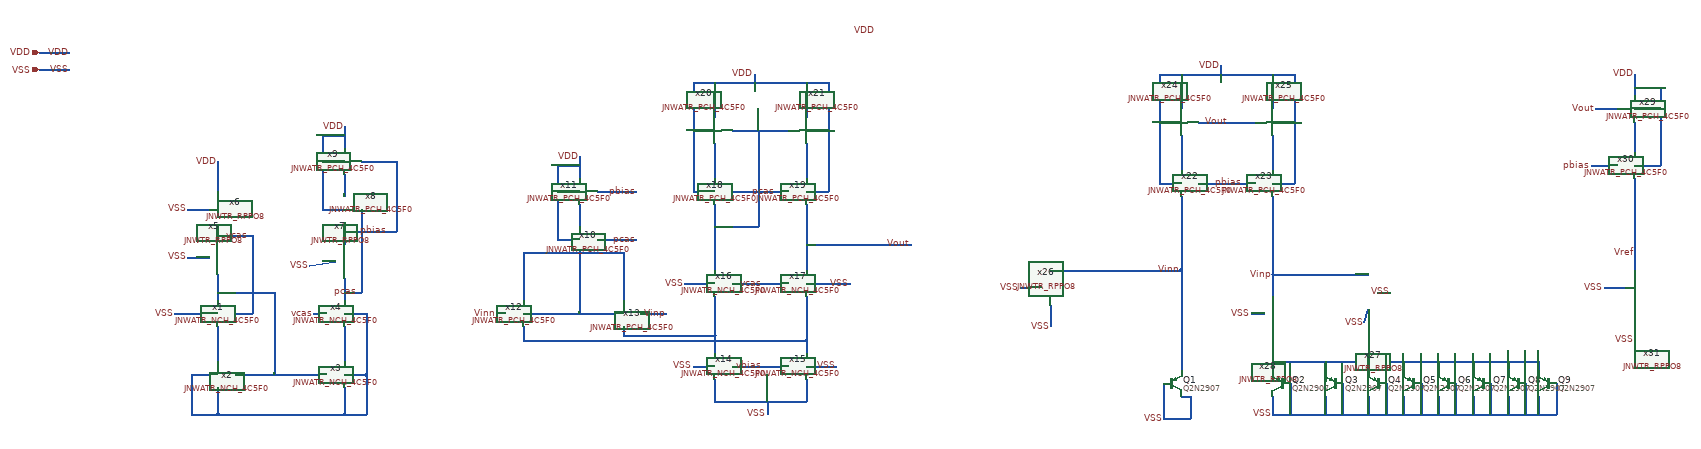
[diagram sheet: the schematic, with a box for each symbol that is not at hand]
v {xschem version=3.4.6 file_version=1.2}
G {}
K {}
V {}
S {sd}
E {}
N -50 30 -50 110 {lab=#net1}
N -10 140 200 140 {lab=#net2}
N -50 -90 -50 -30 {lab=#net2}
N -50 -200 -50 -170 {lab=vcas}
N 240 -80 240 -30 {lab=pcas}
N 240 -210 240 -160 {lab=pbias}
N 240 -320 240 -270 {lab=#net3}
N 240 30 240 110 {lab=#net4}
N -50 170 -50 230 {lab=#net5}
N -50 230 240 230 {lab=#net5}
N 240 170 240 220 {lab=#net5}
N 240 220 240 230 {lab=#net5}
N -110 140 -50 140 {lab=#net5}
N -110 140 -110 230 {lab=#net5}
N -110 230 -50 230 {lab=#net5}
N 240 140 290 140 {lab=#net5}
N 240 230 290 230 {lab=#net5}
N 290 140 290 230 {lab=#net5}
N 290 0 290 140 {lab=#net5}
N 240 0 290 0 {lab=#net5}
N -10 0 30 0 {lab=vcas}
N -50 -180 30 -180 {lab=vcas}
N 30 -180 30 0 {lab=vcas}
N -50 -50 80 -50 {lab=#net2}
N 80 -50 80 140 {lab=#net2}
N -460 -560 -430 -560 {lab=VSS}
N -430 -560 -390 -560 {lab=VSS}
N -120 -130 -70 -130 {lab=VSS}
N -120 -240 -70 -240 {lab=VSS}
N -150 0 -50 0 {lab=VSS}
N 160 -110 220 -120 {lab=VSS}
N -460 -600 -390 -600 {lab=VDD}
N 240 -430 240 -380 {lab=VDD}
N 190 -410 240 -410 {lab=VDD}
N 190 -410 190 -240 {lab=VDD}
N 190 -240 240 -240 {lab=VDD}
N 190 -350 240 -350 {lab=VDD}
N 280 -350 360 -350 {lab=pbias}
N 360 -350 360 -190 {lab=pbias}
N 240 -190 360 -190 {lab=pbias}
N 280 -240 280 -50 {lab=pcas}
N 240 -50 280 -50 {lab=pcas}
N -50 -350 -50 -280 {lab=VDD}
N 170 0 200 0 {lab=vcas}
N 780 -250 780 -200 {lab=#net6}
N 780 -360 780 -310 {lab=VDD}
N 730 -340 780 -340 {lab=VDD}
N 730 -340 730 -170 {lab=VDD}
N 730 -170 780 -170 {lab=VDD}
N 730 -280 780 -280 {lab=VDD}
N 820 -280 910 -280 {lab=pbias}
N 820 -170 910 -170 {lab=pcas}
N 780 -140 880 -140 {lab=#net7}
N 880 -140 880 -30 {lab=#net7}
N 660 -140 780 -140 {lab=#net7}
N 650 -140 650 -30 {lab=#net7}
N 650 -140 660 -140 {lab=#net7}
N 650 0 880 0 {lab=#net7}
N 780 -140 780 0 {lab=#net7}
N 920 0 980 0 {lab=Vinp}
N 590 0 610 0 {lab=Vinn}
N 1130 120 1260 120 {lab=vbias}
N 1130 -70 1260 -70 {lab=vcas}
N 1090 -40 1090 50 {lab=#net8}
N 1300 -40 1300 60 {lab=#net9}
N 1090 80 1090 90 {lab=#net8}
N 880 30 880 50 {lab=#net8}
N 1090 50 1090 80 {lab=#net8}
N 1300 60 1300 90 {lab=#net9}
N 880 50 1090 50 {lab=#net8}
N 650 30 650 50 {lab=#net9}
N 650 50 650 60 {lab=#net9}
N 650 60 1300 60 {lab=#net9}
N 1090 150 1090 200 {lab=VSS}
N 1090 200 1300 200 {lab=VSS}
N 1300 150 1300 200 {lab=VSS}
N 1090 -250 1090 -100 {lab=#net10}
N 1300 -250 1300 -100 {lab=Vout}
N 1130 -280 1260 -280 {lab=pcas}
N 1130 -420 1260 -420 {lab=#net10}
N 1300 -390 1300 -310 {lab=#net11}
N 1090 -390 1090 -310 {lab=#net12}
N 1190 -420 1190 -200 {lab=#net10}
N 1090 -200 1190 -200 {lab=#net10}
N 1040 -280 1090 -280 {lab=VDD}
N 1040 -520 1040 -280 {lab=VDD}
N 1040 -420 1090 -420 {lab=VDD}
N 1300 -280 1350 -280 {lab=VDD}
N 1350 -530 1350 -280 {lab=VDD}
N 1040 -530 1040 -520 {lab=VDD}
N 1300 -420 1350 -420 {lab=VDD}
N 1040 -530 1350 -530 {lab=VDD}
N 1090 -530 1090 -450 {lab=VDD}
N 1300 -530 1300 -450 {lab=VDD}
N 1180 -550 1180 -530 {lab=VDD}
N 1020 -70 1090 -70 {lab=VSS}
N 1300 -70 1400 -70 {lab=VSS}
N 1300 120 1370 120 {lab=VSS}
N 1040 120 1090 120 {lab=VSS}
N 1210 200 1210 230 {lab=VSS}
N 1300 -160 1540 -160 {lab=Vout}
N 2200 -300 2330 -300 {lab=pbias}
N 2200 -440 2330 -440 {lab=Vout}
N 2370 -410 2370 -330 {lab=#net13}
N 2160 -410 2160 -330 {lab=#net14}
N 2110 -300 2160 -300 {lab=VDD}
N 2110 -540 2110 -300 {lab=VDD}
N 2110 -440 2160 -440 {lab=VDD}
N 2370 -300 2420 -300 {lab=VDD}
N 2420 -550 2420 -300 {lab=VDD}
N 2110 -550 2110 -540 {lab=VDD}
N 2370 -440 2420 -440 {lab=VDD}
N 2110 -550 2420 -550 {lab=VDD}
N 2160 -550 2160 -470 {lab=VDD}
N 2370 -550 2370 -470 {lab=VDD}
N 2250 -570 2250 -550 {lab=VDD}
N 2160 -270 2160 -100 {lab=Vinn}
N 2370 -90 2590 -90 {lab=Vinp}
N 1860 -100 2160 -100 {lab=Vinn}
N 2370 -270 2370 -90 {lab=Vinp}
N 2370 -90 2370 -40 {lab=Vinp}
N 2160 -100 2160 130 {lab=Vinn}
N 2370 40 2370 130 {lab=#net15}
N 2980 110 2980 130 {lab=#net15}
N 2370 110 2980 110 {lab=#net15}
N 2830 110 2830 130 {lab=#net15}
N 2910 110 2910 130 {lab=#net15}
N 2750 110 2750 130 {lab=#net15}
N 2670 110 2670 130 {lab=#net15}
N 2590 110 2590 130 {lab=#net15}
N 2490 110 2490 130 {lab=#net15}
N 2370 190 2370 230 {lab=VSS}
N 2370 230 3020 230 {lab=VSS}
N 3020 160 3020 230 {lab=VSS}
N 2910 190 2910 230 {lab=VSS}
N 2980 190 2980 230 {lab=VSS}
N 2950 160 2950 230 {lab=VSS}
N 2870 160 2870 230 {lab=VSS}
N 2830 190 2830 230 {lab=VSS}
N 2750 190 2750 230 {lab=VSS}
N 2790 160 2790 230 {lab=VSS}
N 2670 190 2670 230 {lab=VSS}
N 2710 160 2710 230 {lab=VSS}
N 2590 190 2590 230 {lab=VSS}
N 2630 160 2630 230 {lab=VSS}
N 2530 160 2530 230 {lab=VSS}
N 2490 190 2490 230 {lab=VSS}
N 2410 160 2410 220 {lab=VSS}
N 2410 220 2410 230 {lab=VSS}
N 2120 160 2120 240 {lab=VSS}
N 2120 240 2170 240 {lab=VSS}
N 2160 190 2180 190 {lab=VSS}
N 2170 240 2180 240 {lab=VSS}
N 2180 190 2180 240 {lab=VSS}
N 1790 -60 1840 -60 {lab=VSS}
N 1860 -20 1860 30 {lab=VSS}
N 2320 0 2350 0 {lab=VSS}
N 2580 20 2590 -10 {lab=VSS}
N 2610 -50 2640 -50 {lab=VSS}
N 3200 -440 3200 -370 {lab=#net16}
N 3200 -550 3200 -500 {lab=VDD}
N 3200 -520 3260 -520 {lab=VDD}
N 3260 -520 3260 -340 {lab=VDD}
N 3200 -340 3260 -340 {lab=VDD}
N 3200 -470 3260 -470 {lab=VDD}
N 3110 -470 3160 -470 {lab=Vout}
N 3100 -340 3160 -340 {lab=pbias}
N 3200 -310 3200 -100 {lab=Vref}
N 3200 -20 3200 60 {lab=VSS}
N 3130 -60 3180 -60 {lab=VSS}
C {JNW_ATR_SKY130A/JNWATR_NCH_4C5F0.sym} -10 0 0 1 {name=x1 }
C {JNW_ATR_SKY130A/JNWATR_NCH_4C5F0.sym} -10 140 0 1 {name=x2 }
C {JNW_ATR_SKY130A/JNWATR_NCH_4C5F0.sym} 200 140 0 0 {name=x3 }
C {JNW_ATR_SKY130A/JNWATR_NCH_4C5F0.sym} 200 0 0 0 {name=x4 }
C {JNW_TR_SKY130A/JNWTR_RPPO8.sym} -50 -170 1 0 {name=x5 }
C {JNW_TR_SKY130A/JNWTR_RPPO8.sym} -50 -280 1 0 {name=x6 }
C {JNW_TR_SKY130A/JNWTR_RPPO8.sym} 240 -160 1 0 {name=x7 }
C {JNW_ATR_SKY130A/JNWATR_PCH_4C5F0.sym} 280 -240 0 1 {name=x8 }
C {JNW_ATR_SKY130A/JNWATR_PCH_4C5F0.sym} 280 -350 0 1 {name=x9 }
C {devices/ipin.sym} -460 -560 0 0 {name=p1 lab=VSS}
C {devices/lab_wire.sym} -390 -560 0 0 {name=p2 sig_type=std_logic lab=VSS}
C {devices/lab_wire.sym} -120 -240 0 0 {name=p3 sig_type=std_logic lab=VSS}
C {devices/lab_wire.sym} -120 -130 0 0 {name=p4 sig_type=std_logic lab=VSS}
C {devices/lab_wire.sym} -150 0 0 0 {name=p5 sig_type=std_logic lab=VSS}
C {devices/lab_wire.sym} 160 -110 0 0 {name=p6 sig_type=std_logic lab=VSS}
C {devices/ipin.sym} -460 -600 0 0 {name=p8 lab=VDD}
C {devices/lab_wire.sym} -390 -600 0 0 {name=p9 sig_type=std_logic lab=VDD}
C {devices/lab_wire.sym} 240 -430 0 0 {name=p10 sig_type=std_logic lab=VDD}
C {devices/lab_wire.sym} -50 -350 0 0 {name=p7 sig_type=std_logic lab=VDD}
C {devices/lab_wire.sym} 20 -180 0 0 {name=p11 sig_type=std_logic lab=vcas}
C {devices/lab_wire.sym} 170 0 0 0 {name=p12 sig_type=std_logic lab=vcas}
C {devices/lab_wire.sym} 270 -50 0 0 {name=p13 sig_type=std_logic lab=pcas}
C {devices/lab_wire.sym} 340 -190 0 0 {name=p14 sig_type=std_logic lab=pbias}
C {JNW_ATR_SKY130A/JNWATR_PCH_4C5F0.sym} 820 -170 0 1 {name=x10 }
C {JNW_ATR_SKY130A/JNWATR_PCH_4C5F0.sym} 820 -280 0 1 {name=x11 }
C {devices/lab_wire.sym} 780 -360 0 0 {name=p15 sig_type=std_logic lab=VDD}
C {devices/lab_wire.sym} 910 -280 0 0 {name=p16 sig_type=std_logic lab=pbias}
C {devices/lab_wire.sym} 910 -170 0 0 {name=p17 sig_type=std_logic lab=pcas}
C {JNW_ATR_SKY130A/JNWATR_PCH_4C5F0.sym} 610 0 0 0 {name=x12 }
C {JNW_ATR_SKY130A/JNWATR_PCH_4C5F0.sym} 920 0 0 1 {name=x13 }
C {devices/lab_wire.sym} 590 0 0 0 {name=p18 sig_type=std_logic lab=Vinn}
C {devices/lab_wire.sym} 980 0 0 0 {name=p19 sig_type=std_logic lab=Vinp}
C {JNW_ATR_SKY130A/JNWATR_NCH_4C5F0.sym} 1130 120 0 1 {name=x14 }
C {JNW_ATR_SKY130A/JNWATR_NCH_4C5F0.sym} 1260 120 0 0 {name=x15 }
C {JNW_ATR_SKY130A/JNWATR_NCH_4C5F0.sym} 1130 -70 0 1 {name=x16 }
C {JNW_ATR_SKY130A/JNWATR_NCH_4C5F0.sym} 1260 -70 0 0 {name=x17 }
C {JNW_ATR_SKY130A/JNWATR_PCH_4C5F0.sym} 1130 -280 0 1 {name=x18 }
C {JNW_ATR_SKY130A/JNWATR_PCH_4C5F0.sym} 1260 -280 0 0 {name=x19 }
C {JNW_ATR_SKY130A/JNWATR_PCH_4C5F0.sym} 1130 -420 0 1 {name=x20 }
C {JNW_ATR_SKY130A/JNWATR_PCH_4C5F0.sym} 1260 -420 0 0 {name=x21 }
C {devices/lab_wire.sym} 1180 -550 0 0 {name=p20 sig_type=std_logic lab=VDD}
C {devices/lab_wire.sym} 1020 -70 0 0 {name=p21 sig_type=std_logic lab=VSS}
C {devices/lab_wire.sym} 1400 -70 0 0 {name=p22 sig_type=std_logic lab=VSS}
C {devices/lab_wire.sym} 1040 120 0 0 {name=p23 sig_type=std_logic lab=VSS}
C {devices/lab_wire.sym} 1370 120 0 0 {name=p24 sig_type=std_logic lab=VSS}
C {devices/lab_wire.sym} 1210 230 0 0 {name=p25 sig_type=std_logic lab=VSS}
C {devices/lab_wire.sym} 1230 -280 0 0 {name=p26 sig_type=std_logic lab=pcas}
C {devices/lab_wire.sym} 1200 -70 0 0 {name=p27 sig_type=std_logic lab=vcas}
C {devices/lab_wire.sym} 1200 120 0 0 {name=p28 sig_type=std_logic lab=vbias}
C {devices/lab_wire.sym} 1540 -160 0 0 {name=p29 sig_type=std_logic lab=Vout}
C {JNW_ATR_SKY130A/JNWATR_PCH_4C5F0.sym} 2200 -300 0 1 {name=x22 }
C {JNW_ATR_SKY130A/JNWATR_PCH_4C5F0.sym} 2330 -300 0 0 {name=x23 }
C {JNW_ATR_SKY130A/JNWATR_PCH_4C5F0.sym} 2200 -440 0 1 {name=x24 }
C {JNW_ATR_SKY130A/JNWATR_PCH_4C5F0.sym} 2330 -440 0 0 {name=x25 }
C {devices/lab_wire.sym} 2250 -570 0 0 {name=p30 sig_type=std_logic lab=VDD}
C {devices/lab_wire.sym} 2300 -300 0 0 {name=p31 sig_type=std_logic lab=pbias}
C {JNW_TR_SKY130A/JNWTR_RPPO8.sym} 1860 -100 1 0 {name=x26 }
C {JNW_TR_SKY130A/JNWTR_RPPO8.sym} 2590 -90 3 1 {name=x27 }
C {JNW_TR_SKY130A/JNWTR_RPPO8.sym} 2370 -40 1 0 {name=x28 }
C {devices/pnp.sym} 2140 160 0 0 {name=Q1
model=Q2N2907
device=2N2907
footprint=TO92
area=1
m=1}
C {devices/pnp.sym} 2390 160 0 1 {name=Q2
model=Q2N2907
device=2N2907
footprint=TO92
area=1
m=1}
C {devices/pnp.sym} 2510 160 0 1 {name=Q3
model=Q2N2907
device=2N2907
footprint=TO92
area=1
m=1}
C {devices/pnp.sym} 2610 160 0 1 {name=Q4
model=Q2N2907
device=2N2907
footprint=TO92
area=1
m=1}
C {devices/pnp.sym} 2690 160 0 1 {name=Q5
model=Q2N2907
device=2N2907
footprint=TO92
area=1
m=1}
C {devices/pnp.sym} 2770 160 0 1 {name=Q6
model=Q2N2907
device=2N2907
footprint=TO92
area=1
m=1}
C {devices/pnp.sym} 2850 160 0 1 {name=Q7
model=Q2N2907
device=2N2907
footprint=TO92
area=1
m=1}
C {devices/pnp.sym} 2930 160 0 1 {name=Q8
model=Q2N2907
device=2N2907
footprint=TO92
area=1
m=1}
C {devices/pnp.sym} 3000 160 0 1 {name=Q9
model=Q2N2907
device=2N2907
footprint=TO92
area=1
m=1}
C {devices/lab_wire.sym} 1790 -60 0 0 {name=p32 sig_type=std_logic lab=VSS}
C {devices/lab_wire.sym} 1860 30 0 0 {name=p33 sig_type=std_logic lab=VSS}
C {devices/lab_wire.sym} 2120 240 0 0 {name=p34 sig_type=std_logic lab=VSS}
C {devices/lab_wire.sym} 2370 230 0 0 {name=p35 sig_type=std_logic lab=VSS}
C {devices/lab_wire.sym} 2320 0 0 0 {name=p36 sig_type=std_logic lab=VSS}
C {devices/lab_wire.sym} 2580 20 0 0 {name=p37 sig_type=std_logic lab=VSS}
C {devices/lab_wire.sym} 2640 -50 0 0 {name=p38 sig_type=std_logic lab=VSS}
C {devices/lab_wire.sym} 2270 -440 0 0 {name=p39 sig_type=std_logic lab=Vout}
C {devices/lab_wire.sym} 2370 -90 0 0 {name=p40 sig_type=std_logic lab=Vinp}
C {devices/lab_wire.sym} 2160 -100 0 0 {name=p41 sig_type=std_logic lab=Vinn}
C {JNW_ATR_SKY130A/JNWATR_PCH_4C5F0.sym} 3160 -470 0 0 {name=x29 }
C {JNW_ATR_SKY130A/JNWATR_PCH_4C5F0.sym} 3160 -340 0 0 {name=x30 }
C {devices/lab_wire.sym} 1460 -650 0 0 {name=p42 sig_type=std_logic lab=VDD}
C {devices/lab_wire.sym} 3200 -550 0 0 {name=p43 sig_type=std_logic lab=VDD}
C {devices/lab_wire.sym} 3110 -470 0 0 {name=p44 sig_type=std_logic lab=Vout}
C {devices/lab_wire.sym} 3100 -340 0 0 {name=p45 sig_type=std_logic lab=pbias}
C {JNW_TR_SKY130A/JNWTR_RPPO8.sym} 3200 -100 1 0 {name=x31 }
C {devices/lab_wire.sym} 3130 -60 0 0 {name=p46 sig_type=std_logic lab=VSS}
C {devices/lab_wire.sym} 3200 60 0 0 {name=p47 sig_type=std_logic lab=VSS}
C {devices/lab_wire.sym} 3200 -140 0 0 {name=p48 sig_type=std_logic lab=Vref}
